VERSION 5.8 ;
BUSBITCHARS "[]" ;
DIVIDERCHAR "/" ;
CLEARANCEMEASURE EUCLIDEAN ;

SITE coresite_DH_P
    SIZE 0.0450 BY 0.2880 ;
    CLASS CORE ;
    SYMMETRY X Y ;
END coresite_DH_P

SITE coresite_DH_N
    SIZE 0.0450 BY 0.2880 ;
    CLASS CORE ;
    SYMMETRY X Y ;
END coresite_DH_N

SITE coresite
    SIZE 0.0450 BY 0.1440 ;
    CLASS CORE ;
    SYMMETRY X Y ;
END coresite

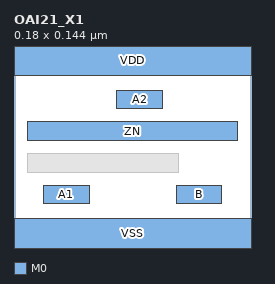
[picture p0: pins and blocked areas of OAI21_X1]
MACRO OAI21_X1
  CLASS CORE ;
  ORIGIN 0 0 ;
  FOREIGN OAI21_X1 0 0 ;
  SIZE 0.1800 BY 0.1440 ;
  SYMMETRY X Y ;
  SITE coresite ;
  PIN A1
    DIRECTION INPUT ;
    USE SIGNAL ;
    PORT
      LAYER M0 ;
        RECT 0.0225 0.0430 0.0570 0.0290 ;
    END
  END A1
  PIN B
    DIRECTION INPUT ;
    USE SIGNAL ;
    PORT
      LAYER M0 ;
        RECT 0.1230 0.0430 0.1575 0.0290 ;
    END
  END B
  PIN ZN
    DIRECTION OUTPUT ;
    USE SIGNAL ;
    PORT
      LAYER M0 ;
        RECT 0.0105 0.0910 0.1695 0.0770 ;
    END
  END ZN
  PIN A2
    DIRECTION INPUT ;
    USE SIGNAL ;
    PORT
      LAYER M0 ;
        RECT 0.0780 0.1150 0.1125 0.1010 ;
    END
  END A2
  PIN VDD
    DIRECTION INOUT ;
    USE POWER ;
    SHAPE ABUTMENT ;
    PORT
      LAYER M0 ;
        RECT 0.0000 0.1260 0.1800 0.1620 ;
    END
  END VDD
  PIN VSS
    DIRECTION INOUT ;
    USE GROUND ;
    SHAPE ABUTMENT ;
    PORT
      LAYER M0 ;
        RECT 0.0000 -0.0180 0.1800 0.0180 ;
    END
  END VSS
  OBS
      LAYER M0 ;
        RECT 0.0105 0.0530 0.1245 0.0670 ;
  END
END OAI21_X1

END LIBRARY
